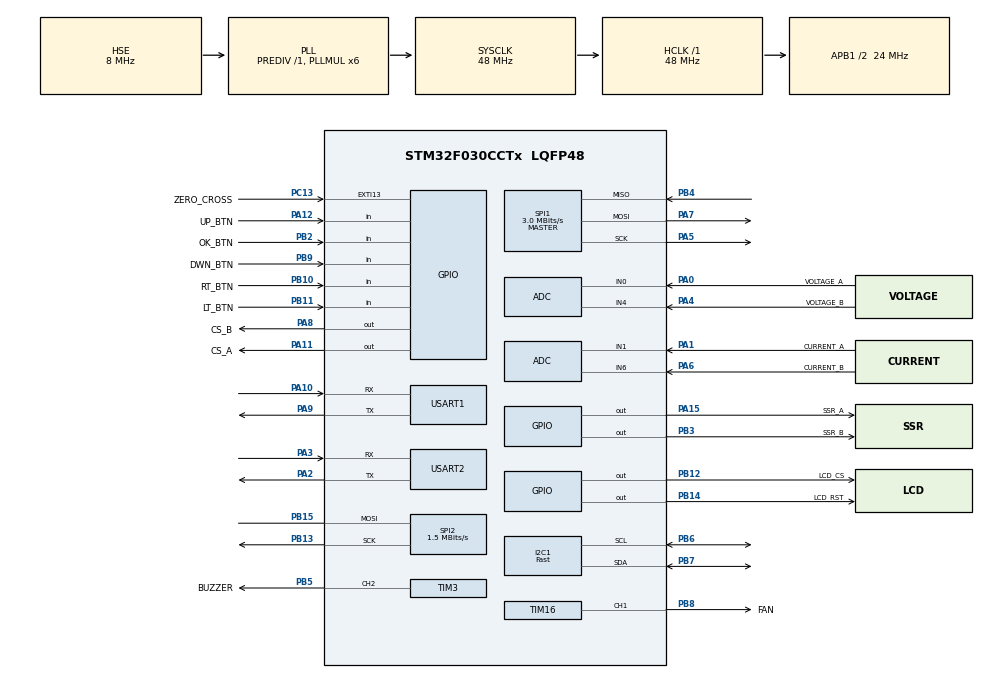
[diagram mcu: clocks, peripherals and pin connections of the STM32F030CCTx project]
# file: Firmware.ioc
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ADC.ContinuousConvMode=DISABLE
ADC.DMAContinuousRequests=DISABLE
ADC.EOCSelection=ADC_EOC_SEQ_CONV
ADC.EnableAnalogWatchDog=false
ADC.ExternalTrigConv=ADC_EXTERNALTRIGCONV_T15_TRGO
ADC.Overrun=ADC_OVR_DATA_OVERWRITTEN
ADC.SamplingTime=ADC_SAMPLETIME_7CYCLES_5
ADC.ScanConvMode=ADC_SCAN_DIRECTION_FORWARD
Dma.ADC.0.Direction=DMA_PERIPH_TO_MEMORY
Dma.ADC.0.Instance=DMA1_Channel1
Dma.ADC.0.MemDataAlignment=DMA_MDATAALIGN_HALFWORD
Dma.ADC.0.MemInc=DMA_MINC_ENABLE
Dma.ADC.0.Mode=DMA_CIRCULAR
Dma.ADC.0.PeriphDataAlignment=DMA_PDATAALIGN_HALFWORD
Dma.ADC.0.PeriphInc=DMA_PINC_DISABLE
Dma.ADC.0.Priority=DMA_PRIORITY_HIGH
Dma.Request0=ADC
I2C1.Analog_Filter=I2C_ANALOGFILTER_ENABLE
I2C1.I2C_Speed_Mode=I2C_Fast
I2C1.Speed=400
I2C1.Timing=0x0000020B
Mcu.Family=STM32F0
Mcu.Name=STM32F030CCTx
Mcu.Package=LQFP48
NVIC.DMA1_Channel1_IRQn=true\:0\:0\:true\:false\:true\:false\:true\:true
NVIC.EXTI4_15_IRQn=true\:0\:0\:false\:false\:true\:true\:true\:false
NVIC.I2C1_IRQn=true\:0\:0\:false\:false\:true\:true\:true\:true
NVIC.RCC_IRQn=true\:0\:0\:false\:false\:true\:true\:false\:true
NVIC.SPI2_IRQn=true\:0\:0\:false\:false\:true\:true\:true\:true
NVIC.TIM15_IRQn=true\:1\:0\:true\:false\:true\:true\:true\:true
NVIC.TIM17_IRQn=true\:0\:0\:false\:false\:true\:true\:true\:true
NVIC.TIM6_IRQn=true\:0\:0\:false\:false\:true\:true\:true\:true
NVIC.TIM7_IRQn=true\:0\:0\:false\:false\:true\:true\:true\:true
NVIC.USART1_IRQn=true\:0\:0\:false\:false\:true\:true\:true\:true
PA0.GPIO_Label=VOLTAGE_A
PA0.Mode=IN0
PA0.Signal=ADC_IN0
PA1.GPIO_Label=CURRENT_A
PA1.Mode=IN1
PA1.Signal=ADC_IN1
PA10.Mode=Asynchronous
PA10.Signal=USART1_RX
PA11.GPIO_Label=CS_A
PA11.Signal=GPIO_Output
PA12.GPIO_Label=UP_BTN
PA12.Signal=GPIO_Input
PA13.Mode=Serial_Wire
PA13.Signal=SYS_SWDIO
PA14.Mode=Serial_Wire
PA14.Signal=SYS_SWCLK
PA15.GPIO_Label=SSR_A
PA15.GPIO_Speed=GPIO_SPEED_FREQ_HIGH
PA15.Signal=GPIO_Output
PA2.Mode=Asynchronous
PA2.Signal=USART2_TX
PA3.Mode=Asynchronous
PA3.Signal=USART2_RX
PA4.GPIO_Label=VOLTAGE_B
PA4.Mode=IN4
PA4.Signal=ADC_IN4
PA5.Mode=Full_Duplex_Master
PA5.Signal=SPI1_SCK
PA6.GPIO_Label=CURRENT_B
PA6.Mode=IN6
PA6.Signal=ADC_IN6
PA7.Mode=Full_Duplex_Master
PA7.Signal=SPI1_MOSI
PA8.GPIO_Label=CS_B
PA8.Signal=GPIO_Output
PA9.Mode=Asynchronous
PA9.Signal=USART1_TX
PB0.GPIO_Label=NTC_A
PB0.Signal=ADC_IN8
PB1.GPIO_Label=NTC_B
PB1.Signal=ADC_IN9
PB10.GPIO_Label=RT_BTN
PB10.Signal=GPIO_Input
PB11.GPIO_Label=LT_BTN
PB11.Signal=GPIO_Input
PB12.GPIO_Label=LCD_CS
PB12.Signal=GPIO_Output
PB13.Mode=Simplex_Bidirectional_Master
PB13.Signal=SPI2_SCK
PB14.GPIO_Label=LCD_RST
PB14.Signal=GPIO_Output
PB15.Mode=Simplex_Bidirectional_Master
PB15.Signal=SPI2_MOSI
PB2.GPIO_Label=OK_BTN
PB2.Signal=GPIO_Input
PB3.GPIO_Label=SSR_B
PB3.GPIO_Speed=GPIO_SPEED_FREQ_HIGH
PB3.Signal=GPIO_Output
PB4.Mode=Full_Duplex_Master
PB4.Signal=SPI1_MISO
PB5.GPIO_Label=BUZZER
PB5.Signal=S_TIM3_CH2
PB6.Mode=I2C
PB6.Signal=I2C1_SCL
PB7.Mode=I2C
PB7.Signal=I2C1_SDA
PB8.GPIO_Label=FAN
PB8.Signal=S_TIM16_CH1
PB9.GPIO_Label=DWN_BTN
PB9.Signal=GPIO_Input
PC13.GPIO_Label=ZERO_CROSS
PC13.GPIO_ModeDefaultEXTI=GPIO_MODE_IT_RISING
PC13.GPIO_PuPd=GPIO_NOPULL
PC13.Signal=GPXTI13
PC14OSC32_IN.GPIO_Label=RE_485
PC14OSC32_IN.Signal=GPIO_Output
PC15OSC32_OUT.GPIO_Label=DE_485
PC15OSC32_OUT.Signal=GPIO_Output
PF0-OSC_IN.Mode=HSE-External-Oscillator
PF0-OSC_IN.Signal=RCC_OSC_IN
PF1-OSC_OUT.Mode=HSE-External-Oscillator
PF1-OSC_OUT.Signal=RCC_OSC_OUT
ProjectManager.HeapSize=0x200
ProjectManager.StackSize=0x200
ProjectManager.TargetToolchain=Makefile
RCC.AHBFreq_Value=48000000
RCC.APB1CLKDivider=RCC_HCLK_DIV2
RCC.APB1Freq_Value=24000000
RCC.APB1TimFreq_Value=48000000
RCC.HCLKFreq_Value=48000000
RCC.PLLMUL=RCC_PLL_MUL6
RCC.PLLSourceVirtual=RCC_PLLSOURCE_HSE
RCC.SYSCLKFreq_VALUE=48000000
RCC.SYSCLKSource=RCC_SYSCLKSOURCE_PLLCLK
RCC.Usart1ClockSelection=RCC_USART1CLKSOURCE_SYSCLK
SH.S_TIM16_CH1.0=TIM16_CH1,PWM Generation1 CH1
SH.S_TIM3_CH2.0=TIM3_CH2,PWM Generation2 CH2
SPI1.BaudRatePrescaler=SPI_BAUDRATEPRESCALER_8
SPI1.CalculateBaudRate=3.0 MBits/s
SPI1.DataSize=SPI_DATASIZE_16BIT
SPI1.Direction=SPI_DIRECTION_2LINES
SPI1.Mode=SPI_MODE_MASTER
SPI1.VirtualType=VM_MASTER
SPI2.BaudRatePrescaler=SPI_BAUDRATEPRESCALER_16
SPI2.CLKPhase=SPI_PHASE_2EDGE
SPI2.CLKPolarity=SPI_POLARITY_HIGH
SPI2.CalculateBaudRate=1.5 MBits/s
SPI2.DataSize=SPI_DATASIZE_8BIT
SPI2.Direction=SPI_DIRECTION_1LINE
SPI2.Mode=SPI_MODE_MASTER
SPI2.VirtualType=VM_MASTER
TIM15.AutoReloadPreload=TIM_AUTORELOAD_PRELOAD_ENABLE
TIM15.Period=59999
TIM15.Prescaler=5
TIM15.TIM_MasterOutputTrigger=TIM_TRGO_UPDATE
TIM15.TIM_MasterSlaveMode=TIM_MASTERSLAVEMODE_DISABLE
TIM16.Channel=TIM_CHANNEL_1
TIM17.AutoReloadPreload=TIM_AUTORELOAD_PRELOAD_ENABLE
TIM17.Channel=TIM_CHANNEL_1
TIM17.Period=500-1
TIM17.Prescaler=48000-1
TIM3.AutoReloadPreload=TIM_AUTORELOAD_PRELOAD_DISABLE
TIM3.Channel-PWM\ Generation2\ CH2=TIM_CHANNEL_2
TIM3.Period=1000
TIM3.Prescaler=47
TIM6.AutoReloadPreload=TIM_AUTORELOAD_PRELOAD_ENABLE
TIM6.Period=62499
TIM6.Prescaler=767
TIM7.AutoReloadPreload=TIM_AUTORELOAD_PRELOAD_ENABLE
TIM7.Period=0xffff-1
TIM7.Prescaler=48-1
USART1.VirtualMode-Asynchronous=VM_ASYNC
USART2.VirtualMode-Asynchronous=VM_ASYNC
VP_TIM15_VS_ClockSourceINT.Mode=Internal
VP_TIM16_VS_ClockSourceINT.Mode=Enable_Timer
VP_TIM17_VS_ClockSourceINT.Mode=Enable_Timer
VP_TIM17_VS_no_output1.Mode=Output Compare1 No Output
VP_TIM6_VS_ClockSourceINT.Mode=Enable_Timer
VP_TIM7_VS_ClockSourceINT.Mode=Enable_Timer
board=custom

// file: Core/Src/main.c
/* USER CODE BEGIN Header */
/**
  ******************************************************************************
  * @file           : main.c
  * @brief          : Main program body
  ******************************************************************************
  * @attention
  *
  * Copyright (c) 2023 STMicroelectronics.
  * All rights reserved.
  *
  * This software is licensed under terms that can be found in the LICENSE file
  * in the root directory of this software component.
  * If no LICENSE file comes with this software, it is provided AS-IS.
  *
  ******************************************************************************
  */
/* USER CODE END Header */
#include "main.h"

/* USER CODE BEGIN Includes */
#include <stdio.h>
#include "stdbool.h"
#include "math.h"
#include "string.h"
#include "stm32_max6675.h"
#include "GEVA.h"
#include "stm32_ST7920_spi.h"
//#include "phase_control.h"  //unsuitable with current ssr
#include "power_modulator.h"
#include "pid.h"
#include "adc.h"
#include "buttons_definition.h"
#include "menu.h"
#include "cycle.h"
#include "icons.h"
#include "flash_writer.h"

/* USER CODE END Includes */

ADC_HandleTypeDef hadc;
DMA_HandleTypeDef hdma_adc;

I2C_HandleTypeDef hi2c1;

SPI_HandleTypeDef hspi1;
SPI_HandleTypeDef hspi2;

TIM_HandleTypeDef htim3;
TIM_HandleTypeDef htim6;
TIM_HandleTypeDef htim7;
TIM_HandleTypeDef htim15;
TIM_HandleTypeDef htim16;
TIM_HandleTypeDef htim17;

UART_HandleTypeDef huart1;
UART_HandleTypeDef huart2;

/* USER CODE BEGIN PV */

/*
timers definition

TIM3: BUZZER PWM
TIM6: 1s temperature reading timer
TIM7: us timer for delay_us()
TIM15: adc trigger 1khz
TIM16: FAN PWM
TIM17: lcd refresh
*/

//video buffer
video_buffer vb;

//thermocouple amplifiers
max6675 tc_A;
max6675 tc_B;
float current_temp; //main temperature used for computation

//chart line
data_container target_temp_chart;
data_container current_temp_chart;

//timers call back flags
volatile uint8_t lcd_refresh_elapsed = 0;
volatile uint8_t second_elapsed = 0;
volatile uint8_t zero_crossed = 0;

//temperature controller

//pid tuning variables
float Kp = 0.0f;
float Ki = 0.0f;
float Kd = 0.0f;

pid_controller temp_pid;
volatile uint8_t power_pct = 0;
float target_temp = 0.0f;
volatile uint8_t crossing_cnt = 0;

reflow_profile temp_curves[3];
int reflow_profile_index;

#define NUM_CHANNELS   4
#define SAMPLES_PER_CHANNEL 1000  // 500Hz x 2 seconds
#define TOTAL_SAMPLES 32 //SAMPLES_PER_CHANNEL*NUM_CHANNELS

uint16_t adc_values[TOTAL_SAMPLES]={0};

float f = 0.0f;
float Vrms = 0.0f;

//cycle time keeping
hilv_time hl_t;

//menu structure
Menu menu;

//cycle manager
Cycle operation_cycle;

/* USER CODE END PV */

void SystemClock_Config(void);
static void MX_GPIO_Init(void);
static void MX_DMA_Init(void);
static void MX_I2C1_Init(void);
static void MX_USART1_UART_Init(void);
static void MX_USART2_UART_Init(void);
static void MX_ADC_Init(void);
static void MX_SPI1_Init(void);
static void MX_SPI2_Init(void);
static void MX_TIM3_Init(void);
static void MX_TIM16_Init(void);
static void MX_TIM17_Init(void);
static void MX_TIM15_Init(void);
static void MX_TIM7_Init(void);
static void MX_TIM6_Init(void);

/* USER CODE BEGIN 0 */

/* ===============================SERVICE FUNCTIONS & VARS    DO NOT DELETE====================================== */

//timers callback
void HAL_TIM_PeriodElapsedCallback(TIM_HandleTypeDef *htim) {

  if (htim->Instance == TIM17) //lcd refresh
    lcd_refresh_elapsed = 1;

  if(htim->Instance == TIM6)  //1 sec elapsed. used for temperature reading
    second_elapsed = 1;

}

//stuff related to power goes in here --->  ZERO crossing callback

void HAL_GPIO_EXTI_Callback(uint16_t GPIO_Pin) {
    if (GPIO_Pin == ZERO_CROSS_Pin) {
      zero_crossed = 1;
      crossing_cnt++;
      power_modulator_set(power_pct, &crossing_cnt);
    }

}

void parse_int(uint16_t num, uint16_t filtered, char *output, char start_c, char end_c ){
  sprintf(output, "%c%d,%d%c", start_c, filtered, num, end_c);
}

void delay_us(uint32_t delay) {

  uint32_t cnt_start = htim7.Instance->CNT;

  while( ( htim7.Instance->CNT - cnt_start) < delay ) {}

}

void heating_animation(){

  static bool heating_animation_frame;

  heating_animation_frame = !heating_animation_frame;
  menu.tabs_vect[TAB_MAIN].items[STATUS].item_data.icon = (heating_animation_frame) ? &heating : &not_heating; //heating animation

}

void heating_animation_clear(){
  if(menu.current_tab == TAB_MAIN)
    clear_sector(menu.tabs_vect[TAB_MAIN].items[STATUS].pos_x,menu.tabs_vect[TAB_MAIN].items[STATUS].pos_y,16,16,&vb);
}

/* ================================================================================================================ */

/* USER CODE END 0 */

int main(void)
{

  /* MCU Configuration--------------------------------------------------------*/

  /* Reset of all peripherals, Initializes the Flash interface and the Systick. */
  HAL_Init();

  /* Configure the system clock */
  SystemClock_Config();

  /* Initialize all configured peripherals */
  MX_GPIO_Init();
  MX_DMA_Init();
  MX_I2C1_Init();
  MX_USART1_UART_Init();
  MX_USART2_UART_Init();
  MX_ADC_Init();
  MX_SPI1_Init();
  MX_SPI2_Init();
  MX_TIM3_Init();
  MX_TIM16_Init();
  MX_TIM17_Init();
  MX_TIM15_Init();
  MX_TIM7_Init();
  MX_TIM6_Init();
  /* USER CODE BEGIN 2 */

/* =================================================video buffer init============================================== */

  init_buf(&vb,128,64);
  set_mode(NORMAL,&vb);
  set_orientation(LANDSCAPE,&vb);

/* ===============================================chart parameter================================================== */

  current_temp_chart.o_x = 3;
  current_temp_chart.o_y = 13;
  current_temp_chart.type = LINE;
  current_temp_chart.dim_x = 104;
  current_temp_chart.dim_y_neg = 0;
  current_temp_chart.dim_y_pos = 37;
  current_temp_chart.max = 300;
  current_temp_chart.min = 0;
  current_temp_chart.x_division = 52;

  target_temp_chart.o_x = 3;
  target_temp_chart.o_y = 13;
  target_temp_chart.type = LINE_CHUNK;
  target_temp_chart.dim_x = 104;
  target_temp_chart.dim_y_neg = 0;
  target_temp_chart.dim_y_pos = 37;
  target_temp_chart.max = 300;
  target_temp_chart.min = 0;
  target_temp_chart.x_division = 52;
  target_temp_chart.max_x = 280;

/* ====================================================display init================================================ */

  init_display(hspi2,LCD_CS_GPIO_Port,LCD_RST_Pin,LCD_CS_GPIO_Port,LCD_CS_Pin);
  HAL_TIM_Base_Start_IT(&htim17); //timer refresh lcd avvio

/* ====================================================menu icons init============================================= */

  menu_init();

/* ==============================================thermocouple amplifier init======================================= */

  max6675_init(&tc_A,CS_A_GPIO_Port,CS_A_Pin,&hspi1);
  max6675_init(&tc_B,CS_B_GPIO_Port,CS_B_Pin,&hspi1);
  HAL_TIM_Base_Start_IT(&htim6); //timer lettura temp avvio

/* ================================================buttons init==================================================== */
  input_buttons_definition();

/* ==============================================power modulator init============================================== */

  power_modulator_init(SSR_A_GPIO_Port,SSR_A_Pin,SSR_B_GPIO_Port,SSR_B_Pin);
  HAL_NVIC_EnableIRQ(EXTI4_15_IRQn);

/* ==================================================pid controller init=========================================== */

  Kp = flash_read_float(KP_DATA_FLASH_ADDRESS);
  Ki = flash_read_float(KI_DATA_FLASH_ADDRESS);
  Kd = flash_read_float(KD_DATA_FLASH_ADDRESS);

  pid_init(&temp_pid, Kp, Ki, Kd, 1.0); // kp, ki, kd, dt

/*
  flash_write_float(CURVE_FLASH_INITIAL_ADDRESS, 120.0f, 0);
  flash_write_float(CURVE_FLASH_INITIAL_ADDRESS, 60.0f, 1);
  flash_write_float(CURVE_FLASH_INITIAL_ADDRESS, 150.0f, 2);
  flash_write_float(CURVE_FLASH_INITIAL_ADDRESS, 90.0f, 3);
  flash_write_float(CURVE_FLASH_INITIAL_ADDRESS, 230.0f, 4);
  flash_write_float(CURVE_FLASH_INITIAL_ADDRESS, 40.0f, 5);

  flash_write_float(CURVE_FLASH_INITIAL_ADDRESS, 100.0f, 6);
  flash_write_float(CURVE_FLASH_INITIAL_ADDRESS, 20.0f, 7);
  flash_write_float(CURVE_FLASH_INITIAL_ADDRESS, 120.0f, 8);
  flash_write_float(CURVE_FLASH_INITIAL_ADDRESS, 60.0f, 9);
  flash_write_float(CURVE_FLASH_INITIAL_ADDRESS, 200.0f, 10);
  flash_write_float(CURVE_FLASH_INITIAL_ADDRESS, 30.0f, 11);

  flash_write_float(CURVE_FLASH_INITIAL_ADDRESS, 40.0f, 12);
  flash_write_float(CURVE_FLASH_INITIAL_ADDRESS, 60.0f, 13);
  flash_write_float(CURVE_FLASH_INITIAL_ADDRESS, 40.0f, 14);
  flash_write_float(CURVE_FLASH_INITIAL_ADDRESS, 20.0f, 15);
  flash_write_float(CURVE_FLASH_INITIAL_ADDRESS, 50.0f, 16);
  flash_write_float(CURVE_FLASH_INITIAL_ADDRESS, 90.0f, 17);
*/

  temp_curves[0].preheat_temp = flash_read_float(PREHEAT_TEMP_1_ADDRESS);
  temp_curves[0].preheat_time = flash_read_float(PREHEAT_TIME_1_ADDRESS);
  temp_curves[0].soak_temp = flash_read_float(SOAK_TEMP_1_ADDRESS);
  temp_curves[0].soak_time = flash_read_float(SOAK_TIME_1_ADDRESS);
  temp_curves[0].peak_temp = flash_read_float(PEAK_TEMP_1_ADDRESS);
  temp_curves[0].reflow_time = flash_read_float(REFLOW_TIME_1_ADDRESS);

  temp_curves[1].preheat_temp = flash_read_float(PREHEAT_TEMP_2_ADDRESS);
  temp_curves[1].preheat_time = flash_read_float(PREHEAT_TIME_2_ADDRESS);
  temp_curves[1].soak_temp = flash_read_float(SOAK_TEMP_2_ADDRESS);
  temp_curves[1].soak_time = flash_read_float(SOAK_TIME_2_ADDRESS);
  temp_curves[1].peak_temp = flash_read_float(PEAK_TEMP_2_ADDRESS);
  temp_curves[1].reflow_time = flash_read_float(REFLOW_TIME_2_ADDRESS);

  temp_curves[2].preheat_temp = flash_read_float(PREHEAT_TEMP_3_ADDRESS);
  temp_curves[2].preheat_time = flash_read_float(PREHEAT_TIME_3_ADDRESS);
  temp_curves[2].soak_temp = flash_read_float(SOAK_TEMP_3_ADDRESS);
  temp_curves[2].soak_time = flash_read_float(SOAK_TIME_3_ADDRESS);
  temp_curves[2].peak_temp = flash_read_float(PEAK_TEMP_3_ADDRESS);
  temp_curves[2].reflow_time = flash_read_float(REFLOW_TIME_3_ADDRESS);

/* ==================================================operation cycle init========================================== */

  operation_cycle.cycle_type = CYCLE_MODE_NONE;
  operation_cycle.status = CYCLE_STOP;

/* ==============================================adc transfer init================================================= */

  adc_init(&htim15, &hadc, hdma_adc, adc_values, TOTAL_SAMPLES);

  /* USER CODE END 2 */

  /* Infinite loop */
  /* USER CODE BEGIN WHILE */

  while (1) {

    handle_input(&menu);

    switch (operation_cycle.status) {

    case CYCLE_RUNNING:

      if(second_elapsed){

        current_temp = (max6675_read_temp(tc_B) + max6675_read_temp(tc_A)) / 2.0f;

        target_temp = get_target_temp(&temp_curves[reflow_profile_index-1], operation_cycle.cycle_type, hl_t.seconds_counter);

        if(operation_cycle.cycle_type != CYCLE_MODE_NONE){

          power_pct = pid_compute(&temp_pid,target_temp,current_temp);
          heating_animation();

          if(operation_cycle.cycle_type == CYCLE_MODE_STATIC)
            update_chart(current_temp,&current_temp_chart,&vb);

          if( !(hl_t.seconds_counter%5) && operation_cycle.cycle_type == CYCLE_MODE_CURVE )
            update_chart(current_temp,&current_temp_chart,&vb);

          if(target_temp < 0.1){
            heating_animation_clear();
            menu.tabs_vect[TAB_MAIN].items[STATUS].item_data.icon = &cooling;
          }

        }
        high_lv_update_time(&hl_t);
        hl_t.seconds_counter++;
        second_elapsed = 0;
      }

    break;

    default:
      power_pct = 0;
      heating_animation_clear();
    break;

  }

    /* USER CODE END WHILE */

    /* USER CODE BEGIN 3 */

  /* ============================================ REFRESH LCD ======================================================= */

    if(lcd_refresh_elapsed) { //every half second

        update_display(&vb);
        lcd_refresh_elapsed = 0 ;
      }
  /* ================================================================================================================ */
  }
  /* USER CODE END 3 */
}

void SystemClock_Config(void)
{
  RCC_OscInitTypeDef RCC_OscInitStruct = {0};
  RCC_ClkInitTypeDef RCC_ClkInitStruct = {0};
  RCC_PeriphCLKInitTypeDef PeriphClkInit = {0};

  /** Initializes the RCC Oscillators according to the specified parameters
  * in the RCC_OscInitTypeDef structure.
  */
  RCC_OscInitStruct.OscillatorType = RCC_OSCILLATORTYPE_HSI|RCC_OSCILLATORTYPE_HSI14
                              |RCC_OSCILLATORTYPE_HSE;
  RCC_OscInitStruct.HSEState = RCC_HSE_ON;
  RCC_OscInitStruct.HSIState = RCC_HSI_ON;
  RCC_OscInitStruct.HSI14State = RCC_HSI14_ON;
  RCC_OscInitStruct.HSICalibrationValue = RCC_HSICALIBRATION_DEFAULT;
  RCC_OscInitStruct.HSI14CalibrationValue = 16;
  RCC_OscInitStruct.PLL.PLLState = RCC_PLL_ON;
  RCC_OscInitStruct.PLL.PLLSource = RCC_PLLSOURCE_HSE;
  RCC_OscInitStruct.PLL.PLLMUL = RCC_PLL_MUL6;
  RCC_OscInitStruct.PLL.PREDIV = RCC_PREDIV_DIV1;
  if (HAL_RCC_OscConfig(&RCC_OscInitStruct) != HAL_OK)
  {
    Error_Handler();
  }

  /** Initializes the CPU, AHB and APB buses clocks
  */
  RCC_ClkInitStruct.ClockType = RCC_CLOCKTYPE_HCLK|RCC_CLOCKTYPE_SYSCLK
                              |RCC_CLOCKTYPE_PCLK1;
  RCC_ClkInitStruct.SYSCLKSource = RCC_SYSCLKSOURCE_PLLCLK;
  RCC_ClkInitStruct.AHBCLKDivider = RCC_SYSCLK_DIV1;
  RCC_ClkInitStruct.APB1CLKDivider = RCC_HCLK_DIV2;

  if (HAL_RCC_ClockConfig(&RCC_ClkInitStruct, FLASH_LATENCY_1) != HAL_OK)
  {
    Error_Handler();
  }
  PeriphClkInit.PeriphClockSelection = RCC_PERIPHCLK_USART1|RCC_PERIPHCLK_I2C1;
  PeriphClkInit.Usart1ClockSelection = RCC_USART1CLKSOURCE_SYSCLK;
  PeriphClkInit.I2c1ClockSelection = RCC_I2C1CLKSOURCE_HSI;
  if (HAL_RCCEx_PeriphCLKConfig(&PeriphClkInit) != HAL_OK)
  {
    Error_Handler();
  }
}

static void MX_ADC_Init(void)
{

  ADC_ChannelConfTypeDef sConfig = {0};

  /** Configure the global features of the ADC (Clock, Resolution, Data Alignment and number of conversion)
  */
  hadc.Instance = ADC1;
  hadc.Init.ClockPrescaler = ADC_CLOCK_ASYNC_DIV1;
  hadc.Init.Resolution = ADC_RESOLUTION_12B;
  hadc.Init.DataAlign = ADC_DATAALIGN_RIGHT;
  hadc.Init.ScanConvMode = ADC_SCAN_DIRECTION_FORWARD;
  hadc.Init.EOCSelection = ADC_EOC_SEQ_CONV;
  hadc.Init.LowPowerAutoWait = DISABLE;
  hadc.Init.LowPowerAutoPowerOff = DISABLE;
  hadc.Init.ContinuousConvMode = ENABLE;
  hadc.Init.DiscontinuousConvMode = DISABLE;
  hadc.Init.ExternalTrigConv = ADC_EXTERNALTRIGCONV_T15_TRGO;
  hadc.Init.ExternalTrigConvEdge = ADC_EXTERNALTRIGCONVEDGE_RISING;
  hadc.Init.DMAContinuousRequests = ENABLE;
  hadc.Init.Overrun = ADC_OVR_DATA_PRESERVED;
  if (HAL_ADC_Init(&hadc) != HAL_OK)
  {
    Error_Handler();
  }

  /** Configure for the selected ADC regular channel to be converted.
  */
  sConfig.Channel = ADC_CHANNEL_0;
  sConfig.Rank = ADC_RANK_CHANNEL_NUMBER;
  sConfig.SamplingTime = ADC_SAMPLETIME_7CYCLES_5;
  if (HAL_ADC_ConfigChannel(&hadc, &sConfig) != HAL_OK)
  {
    Error_Handler();
  }

  /** Configure for the selected ADC regular channel to be converted.
  */
  sConfig.Channel = ADC_CHANNEL_1;
  if (HAL_ADC_ConfigChannel(&hadc, &sConfig) != HAL_OK)
  {
    Error_Handler();
  }

  /** Configure for the selected ADC regular channel to be converted.
  */
  sConfig.Channel = ADC_CHANNEL_4;
  if (HAL_ADC_ConfigChannel(&hadc, &sConfig) != HAL_OK)
  {
    Error_Handler();
  }

  /** Configure for the selected ADC regular channel to be converted.
  */
  sConfig.Channel = ADC_CHANNEL_6;
  if (HAL_ADC_ConfigChannel(&hadc, &sConfig) != HAL_OK)
  {
    Error_Handler();
  }
  /* USER CODE BEGIN ADC_Init 2 */

  ADC1->IER |= ADC_IER_EOSIE;

  ADC1->CR |= ADC_CR_ADCAL;
  while (ADC1->CR & ADC_CR_ADCAL);

  /* USER CODE END ADC_Init 2 */

}

static void MX_I2C1_Init(void)
{

  hi2c1.Instance = I2C1;
  hi2c1.Init.Timing = 0x0000020B;
  hi2c1.Init.OwnAddress1 = 0;
  hi2c1.Init.AddressingMode = I2C_ADDRESSINGMODE_7BIT;
  hi2c1.Init.DualAddressMode = I2C_DUALADDRESS_DISABLE;
  hi2c1.Init.OwnAddress2 = 0;
  hi2c1.Init.OwnAddress2Masks = I2C_OA2_NOMASK;
  hi2c1.Init.GeneralCallMode = I2C_GENERALCALL_DISABLE;
  hi2c1.Init.NoStretchMode = I2C_NOSTRETCH_DISABLE;
  if (HAL_I2C_Init(&hi2c1) != HAL_OK)
  {
    Error_Handler();
  }

  /** Configure Analogue filter
  */
  if (HAL_I2CEx_ConfigAnalogFilter(&hi2c1, I2C_ANALOGFILTER_ENABLE) != HAL_OK)
  {
    Error_Handler();
  }

  /** Configure Digital filter
  */
  if (HAL_I2CEx_ConfigDigitalFilter(&hi2c1, 0) != HAL_OK)
  {
    Error_Handler();
  }

}

static void MX_SPI1_Init(void)
{

  /* SPI1 parameter configuration*/
  hspi1.Instance = SPI1;
  hspi1.Init.Mode = SPI_MODE_MASTER;
  hspi1.Init.Direction = SPI_DIRECTION_2LINES;
  hspi1.Init.DataSize = SPI_DATASIZE_16BIT;
  hspi1.Init.CLKPolarity = SPI_POLARITY_LOW;
  hspi1.Init.CLKPhase = SPI_PHASE_1EDGE;
  hspi1.Init.NSS = SPI_NSS_SOFT;
  hspi1.Init.BaudRatePrescaler = SPI_BAUDRATEPRESCALER_8;
  hspi1.Init.FirstBit = SPI_FIRSTBIT_MSB;
  hspi1.Init.TIMode = SPI_TIMODE_DISABLE;
  hspi1.Init.CRCCalculation = SPI_CRCCALCULATION_DISABLE;
  hspi1.Init.CRCPolynomial = 7;
  hspi1.Init.CRCLength = SPI_CRC_LENGTH_DATASIZE;
  hspi1.Init.NSSPMode = SPI_NSS_PULSE_ENABLE;
  if (HAL_SPI_Init(&hspi1) != HAL_OK)
  {
    Error_Handler();
  }

}

static void MX_SPI2_Init(void)
{

  /* SPI2 parameter configuration*/
  hspi2.Instance = SPI2;
  hspi2.Init.Mode = SPI_MODE_MASTER;
  hspi2.Init.Direction = SPI_DIRECTION_1LINE;
  hspi2.Init.DataSize = SPI_DATASIZE_8BIT;
  hspi2.Init.CLKPolarity = SPI_POLARITY_HIGH;
  hspi2.Init.CLKPhase = SPI_PHASE_2EDGE;
  hspi2.Init.NSS = SPI_NSS_SOFT;
  hspi2.Init.BaudRatePrescaler = SPI_BAUDRATEPRESCALER_16;
  hspi2.Init.FirstBit = SPI_FIRSTBIT_MSB;
  hspi2.Init.TIMode = SPI_TIMODE_DISABLE;
  hspi2.Init.CRCCalculation = SPI_CRCCALCULATION_DISABLE;
  hspi2.Init.CRCPolynomial = 7;
  hspi2.Init.CRCLength = SPI_CRC_LENGTH_DATASIZE;
  hspi2.Init.NSSPMode = SPI_NSS_PULSE_DISABLE;
  if (HAL_SPI_Init(&hspi2) != HAL_OK)
  {
    Error_Handler();
  }

}

static void MX_TIM3_Init(void)
{

  TIM_MasterConfigTypeDef sMasterConfig = {0};
  TIM_OC_InitTypeDef sConfigOC = {0};

  htim3.Instance = TIM3;
  htim3.Init.Prescaler = 47;
  htim3.Init.CounterMode = TIM_COUNTERMODE_UP;
  htim3.Init.Period = 1000;
  htim3.Init.ClockDivision = TIM_CLOCKDIVISION_DIV1;
  htim3.Init.AutoReloadPreload = TIM_AUTORELOAD_PRELOAD_DISABLE;
  if (HAL_TIM_PWM_Init(&htim3) != HAL_OK)
  {
    Error_Handler();
  }
  sMasterConfig.MasterOutputTrigger = TIM_TRGO_RESET;
  sMasterConfig.MasterSlaveMode = TIM_MASTERSLAVEMODE_DISABLE;
  if (HAL_TIMEx_MasterConfigSynchronization(&htim3, &sMasterConfig) != HAL_OK)
  {
    Error_Handler();
  }
  sConfigOC.OCMode = TIM_OCMODE_PWM1;
  sConfigOC.Pulse = 0;
  sConfigOC.OCPolarity = TIM_OCPOLARITY_HIGH;
  sConfigOC.OCFastMode = TIM_OCFAST_DISABLE;
  if (HAL_TIM_PWM_ConfigChannel(&htim3, &sConfigOC, TIM_CHANNEL_2) != HAL_OK)
  {
    Error_Handler();
  }
  HAL_TIM_MspPostInit(&htim3);

}

static void MX_TIM6_Init(void)
{

  htim6.Instance = TIM6;
  htim6.Init.Prescaler = 767;
  htim6.Init.CounterMode = TIM_COUNTERMODE_UP;
  htim6.Init.Period = 62499;
  htim6.Init.AutoReloadPreload = TIM_AUTORELOAD_PRELOAD_ENABLE;
  if (HAL_TIM_Base_Init(&htim6) != HAL_OK)
  {
    Error_Handler();
  }

}

static void MX_TIM7_Init(void)
{

  htim7.Instance = TIM7;
  htim7.Init.Prescaler = 48-1;
  htim7.Init.CounterMode = TIM_COUNTERMODE_UP;
  htim7.Init.Period = 0xffff-1;
  htim7.Init.AutoReloadPreload = TIM_AUTORELOAD_PRELOAD_ENABLE;
  if (HAL_TIM_Base_Init(&htim7) != HAL_OK)
  {
    Error_Handler();
  }

}

static void MX_TIM15_Init(void)
{

  TIM_ClockConfigTypeDef sClockSourceConfig = {0};
  TIM_MasterConfigTypeDef sMasterConfig = {0};

  htim15.Instance = TIM15;
  htim15.Init.Prescaler = 4800-1;
  htim15.Init.CounterMode = TIM_COUNTERMODE_UP;
  htim15.Init.Period = 10-1;
  htim15.Init.ClockDivision = TIM_CLOCKDIVISION_DIV1;
  htim15.Init.RepetitionCounter = 0;
  htim15.Init.AutoReloadPreload = TIM_AUTORELOAD_PRELOAD_ENABLE;
  if (HAL_TIM_Base_Init(&htim15) != HAL_OK)
  {
    Error_Handler();
  }
  sClockSourceConfig.ClockSource = TIM_CLOCKSOURCE_INTERNAL;
  if (HAL_TIM_ConfigClockSource(&htim15, &sClockSourceConfig) != HAL_OK)
  {
    Error_Handler();
  }
  sMasterConfig.MasterOutputTrigger = TIM_TRGO_OC1;
  sMasterConfig.MasterSlaveMode = TIM_MASTERSLAVEMODE_DISABLE;
  if (HAL_TIMEx_MasterConfigSynchronization(&htim15, &sMasterConfig) != HAL_OK)
  {
    Error_Handler();
  }

}

static void MX_TIM16_Init(void)
{

  TIM_OC_InitTypeDef sConfigOC = {0};
  TIM_BreakDeadTimeConfigTypeDef sBreakDeadTimeConfig = {0};

  htim16.Instance = TIM16;
  htim16.Init.Prescaler = 0;
  htim16.Init.CounterMode = TIM_COUNTERMODE_UP;
  htim16.Init.Period = 65535;
  htim16.Init.ClockDivision = TIM_CLOCKDIVISION_DIV1;
  htim16.Init.RepetitionCounter = 0;
  htim16.Init.AutoReloadPreload = TIM_AUTORELOAD_PRELOAD_DISABLE;
  if (HAL_TIM_Base_Init(&htim16) != HAL_OK)
  {
    Error_Handler();
  }
  if (HAL_TIM_PWM_Init(&htim16) != HAL_OK)
  {
    Error_Handler();
  }
  sConfigOC.OCMode = TIM_OCMODE_PWM1;
  sConfigOC.Pulse = 0;
  sConfigOC.OCPolarity = TIM_OCPOLARITY_HIGH;
  sConfigOC.OCNPolarity = TIM_OCNPOLARITY_HIGH;
  sConfigOC.OCFastMode = TIM_OCFAST_DISABLE;
  sConfigOC.OCIdleState = TIM_OCIDLESTATE_RESET;
  sConfigOC.OCNIdleState = TIM_OCNIDLESTATE_RESET;
  if (HAL_TIM_PWM_ConfigChannel(&htim16, &sConfigOC, TIM_CHANNEL_1) != HAL_OK)
  {
    Error_Handler();
  }
  sBreakDeadTimeConfig.OffStateRunMode = TIM_OSSR_DISABLE;
  sBreakDeadTimeConfig.OffStateIDLEMode = TIM_OSSI_DISABLE;
  sBreakDeadTimeConfig.LockLevel = TIM_LOCKLEVEL_OFF;
  sBreakDeadTimeConfig.DeadTime = 0;
  sBreakDeadTimeConfig.BreakState = TIM_BREAK_DISABLE;
  sBreakDeadTimeConfig.BreakPolarity = TIM_BREAKPOLARITY_HIGH;
  sBreakDeadTimeConfig.AutomaticOutput = TIM_AUTOMATICOUTPUT_DISABLE;
  if (HAL_TIMEx_ConfigBreakDeadTime(&htim16, &sBreakDeadTimeConfig) != HAL_OK)
  {
    Error_Handler();
  }
  HAL_TIM_MspPostInit(&htim16);

}

static void MX_TIM17_Init(void)
{

  TIM_OC_InitTypeDef sConfigOC = {0};
  TIM_BreakDeadTimeConfigTypeDef sBreakDeadTimeConfig = {0};

  htim17.Instance = TIM17;
  htim17.Init.Prescaler = 48000-1;
  htim17.Init.CounterMode = TIM_COUNTERMODE_UP;
  htim17.Init.Period = 500-1;
  htim17.Init.ClockDivision = TIM_CLOCKDIVISION_DIV1;
  htim17.Init.RepetitionCounter = 0;
  htim17.Init.AutoReloadPreload = TIM_AUTORELOAD_PRELOAD_ENABLE;
  if (HAL_TIM_Base_Init(&htim17) != HAL_OK)
  {
    Error_Handler();
  }
  if (HAL_TIM_OC_Init(&htim17) != HAL_OK)
  {
    Error_Handler();
  }
  sConfigOC.OCMode = TIM_OCMODE_TIMING;
  sConfigOC.Pulse = 0;
  sConfigOC.OCPolarity = TIM_OCPOLARITY_HIGH;
  sConfigOC.OCNPolarity = TIM_OCNPOLARITY_HIGH;
  sConfigOC.OCFastMode = TIM_OCFAST_DISABLE;
  sConfigOC.OCIdleState = TIM_OCIDLESTATE_RESET;
  sConfigOC.OCNIdleState = TIM_OCNIDLESTATE_RESET;
  if (HAL_TIM_OC_ConfigChannel(&htim17, &sConfigOC, TIM_CHANNEL_1) != HAL_OK)
  {
    Error_Handler();
  }
  sBreakDeadTimeConfig.OffStateRunMode = TIM_OSSR_DISABLE;
  sBreakDeadTimeConfig.OffStateIDLEMode = TIM_OSSI_DISABLE;
  sBreakDeadTimeConfig.LockLevel = TIM_LOCKLEVEL_OFF;
  sBreakDeadTimeConfig.DeadTime = 0;
  sBreakDeadTimeConfig.BreakState = TIM_BREAK_DISABLE;
  sBreakDeadTimeConfig.BreakPolarity = TIM_BREAKPOLARITY_HIGH;
  sBreakDeadTimeConfig.AutomaticOutput = TIM_AUTOMATICOUTPUT_DISABLE;
  if (HAL_TIMEx_ConfigBreakDeadTime(&htim17, &sBreakDeadTimeConfig) != HAL_OK)
  {
    Error_Handler();
  }

}

static void MX_USART1_UART_Init(void)
{

  huart1.Instance = USART1;
  huart1.Init.BaudRate = 115200;
  huart1.Init.WordLength = UART_WORDLENGTH_8B;
  huart1.Init.StopBits = UART_STOPBITS_1;
  huart1.Init.Parity = UART_PARITY_NONE;
  huart1.Init.Mode = UART_MODE_TX_RX;
  huart1.Init.HwFlowCtl = UART_HWCONTROL_NONE;
  huart1.Init.OverSampling = UART_OVERSAMPLING_16;
  huart1.Init.OneBitSampling = UART_ONE_BIT_SAMPLE_DISABLE;
  huart1.AdvancedInit.AdvFeatureInit = UART_ADVFEATURE_NO_INIT;
  if (HAL_UART_Init(&huart1) != HAL_OK)
  {
    Error_Handler();
  }

}

static void MX_USART2_UART_Init(void)
{

  huart2.Instance = USART2;
  huart2.Init.BaudRate = 115200;
  huart2.Init.WordLength = UART_WORDLENGTH_8B;
  huart2.Init.StopBits = UART_STOPBITS_1;
  huart2.Init.Parity = UART_PARITY_NONE;
  huart2.Init.Mode = UART_MODE_TX_RX;
  huart2.Init.HwFlowCtl = UART_HWCONTROL_NONE;
  huart2.Init.OverSampling = UART_OVERSAMPLING_16;
  huart2.Init.OneBitSampling = UART_ONE_BIT_SAMPLE_DISABLE;
  huart2.AdvancedInit.AdvFeatureInit = UART_ADVFEATURE_NO_INIT;
  if (HAL_UART_Init(&huart2) != HAL_OK)
  {
    Error_Handler();
  }

}

static void MX_DMA_Init(void)
{

  /* DMA controller clock enable */
  __HAL_RCC_DMA1_CLK_ENABLE();

  /* DMA interrupt init */
  /* DMA1_Channel1_IRQn interrupt configuration */
  HAL_NVIC_SetPriority(DMA1_Channel1_IRQn, 1, 0);
  HAL_NVIC_EnableIRQ(DMA1_Channel1_IRQn);

}

static void MX_GPIO_Init(void)
{
  GPIO_InitTypeDef GPIO_InitStruct = {0};

  /* GPIO Ports Clock Enable */
  __HAL_RCC_GPIOC_CLK_ENABLE();
  __HAL_RCC_GPIOF_CLK_ENABLE();
  __HAL_RCC_GPIOA_CLK_ENABLE();
  __HAL_RCC_GPIOB_CLK_ENABLE();

  /*Configure GPIO pin Output Level */
  HAL_GPIO_WritePin(GPIOC, RE_485_Pin|DE_485_Pin, GPIO_PIN_RESET);

  /*Configure GPIO pin Output Level */
  HAL_GPIO_WritePin(GPIOB, LCD_CS_Pin|LCD_RST_Pin|SSR_B_Pin, GPIO_PIN_RESET);

  /*Configure GPIO pin Output Level */
  HAL_GPIO_WritePin(GPIOA, CS_B_Pin|CS_A_Pin|SSR_A_Pin, GPIO_PIN_RESET);

  /*Configure GPIO pin : ZERO_CROSS_Pin */
  GPIO_InitStruct.Pin = ZERO_CROSS_Pin;
  GPIO_InitStruct.Mode = GPIO_MODE_IT_RISING;
  GPIO_InitStruct.Pull = GPIO_NOPULL;
  HAL_GPIO_Init(ZERO_CROSS_GPIO_Port, &GPIO_InitStruct);

  /*Configure GPIO pins : RE_485_Pin DE_485_Pin */
  GPIO_InitStruct.Pin = RE_485_Pin|DE_485_Pin;
  GPIO_InitStruct.Mode = GPIO_MODE_OUTPUT_PP;
  GPIO_InitStruct.Pull = GPIO_NOPULL;
  GPIO_InitStruct.Speed = GPIO_SPEED_FREQ_LOW;
  HAL_GPIO_Init(GPIOC, &GPIO_InitStruct);

  /*Configure GPIO pins : OK_BTN_Pin RT_BTN_Pin LT_BTN_Pin DWN_BTN_Pin */
  GPIO_InitStruct.Pin = OK_BTN_Pin|RT_BTN_Pin|LT_BTN_Pin|DWN_BTN_Pin;
  GPIO_InitStruct.Mode = GPIO_MODE_INPUT;
  GPIO_InitStruct.Pull = GPIO_NOPULL;
  HAL_GPIO_Init(GPIOB, &GPIO_InitStruct);

  /*Configure GPIO pins : LCD_CS_Pin LCD_RST_Pin */
  GPIO_InitStruct.Pin = LCD_CS_Pin|LCD_RST_Pin;
  GPIO_InitStruct.Mode = GPIO_MODE_OUTPUT_PP;
  GPIO_InitStruct.Pull = GPIO_NOPULL;
  GPIO_InitStruct.Speed = GPIO_SPEED_FREQ_LOW;
  HAL_GPIO_Init(GPIOB, &GPIO_InitStruct);

  /*Configure GPIO pins : CS_B_Pin CS_A_Pin */
  GPIO_InitStruct.Pin = CS_B_Pin|CS_A_Pin;
  GPIO_InitStruct.Mode = GPIO_MODE_OUTPUT_PP;
  GPIO_InitStruct.Pull = GPIO_NOPULL;
  GPIO_InitStruct.Speed = GPIO_SPEED_FREQ_LOW;
  HAL_GPIO_Init(GPIOA, &GPIO_InitStruct);

  /*Configure GPIO pin : UP_BTN_Pin */
  GPIO_InitStruct.Pin = UP_BTN_Pin;
  GPIO_InitStruct.Mode = GPIO_MODE_INPUT;
  GPIO_InitStruct.Pull = GPIO_NOPULL;
  HAL_GPIO_Init(UP_BTN_GPIO_Port, &GPIO_InitStruct);

  /*Configure GPIO pin : SSR_A_Pin */
  GPIO_InitStruct.Pin = SSR_A_Pin;
  GPIO_InitStruct.Mode = GPIO_MODE_OUTPUT_PP;
  GPIO_InitStruct.Pull = GPIO_NOPULL;
  GPIO_InitStruct.Speed = GPIO_SPEED_FREQ_HIGH;
  HAL_GPIO_Init(SSR_A_GPIO_Port, &GPIO_InitStruct);

  /*Configure GPIO pin : SSR_B_Pin */
  GPIO_InitStruct.Pin = SSR_B_Pin;
  GPIO_InitStruct.Mode = GPIO_MODE_OUTPUT_PP;
  GPIO_InitStruct.Pull = GPIO_NOPULL;
  GPIO_InitStruct.Speed = GPIO_SPEED_FREQ_HIGH;
  HAL_GPIO_Init(SSR_B_GPIO_Port, &GPIO_InitStruct);

  /* EXTI interrupt init*/
  HAL_NVIC_SetPriority(EXTI4_15_IRQn, 0, 0);

}

void Error_Handler(void)
{
  __disable_irq();
  while (1)
  {
  }
}
